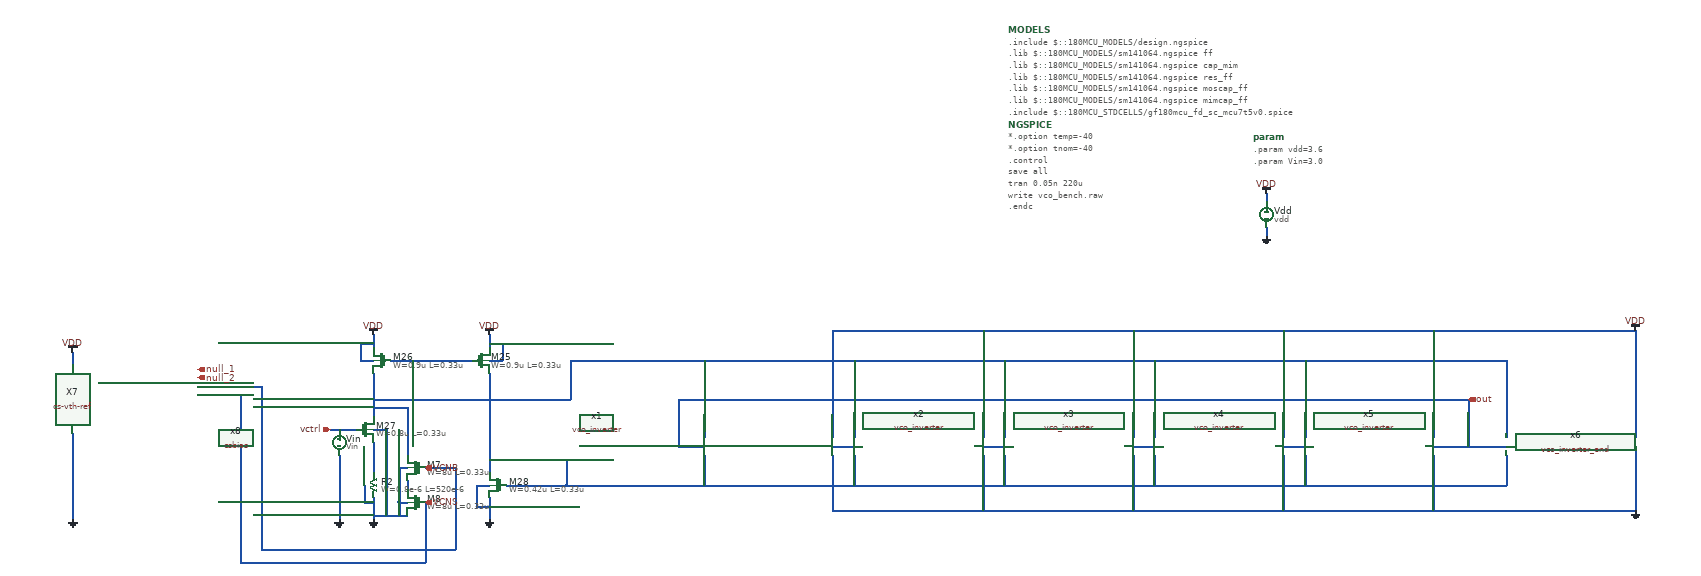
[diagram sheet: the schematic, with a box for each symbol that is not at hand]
v {xschem version=3.4.5 file_version=1.2
}
G {}
K {}
V {}
S {}
E {}
N 300 -460 300 -350 {
lab=out}
N 300 -350 360 -350 {
lab=out}
N 1670 -940 1670 -920 {
lab=VDD}
N 1670 -860 1670 -840 {
lab=GND}
N -410 -520 -410 -420 {
lab=#net1}
N -410 -610 -410 -580 {
lab=VDD}
N -140 -610 -140 -580 {
lab=VDD}
N -140 -590 -110 -590 {
lab=VDD}
N -110 -590 -110 -550 {
lab=VDD}
N -140 -550 -110 -550 {
lab=VDD}
N -440 -550 -410 -550 {
lab=VDD}
N -440 -590 -440 -550 {
lab=VDD}
N -440 -590 -410 -590 {
lab=VDD}
N 50 -550 50 -460 {
lab=#net1}
N -140 -520 -140 -290 {
lab=#net2}
N -140 -230 -140 -180 {
lab=GND}
N -410 -360 -410 -290 {
lab=#net3}
N -410 -230 -410 -180 {
lab=GND}
N -410 -390 -380 -390 {
lab=GND}
N -380 -390 -380 -200 {
lab=GND}
N -410 -440 -330 -440 {
lab=#net1}
N -330 -440 -330 -330 {
lab=#net1}
N -170 -260 -140 -260 {
lab=GND}
N -170 -210 -140 -210 {
lab=GND}
N -140 -320 40 -320 {
lab=#net2}
N -100 -260 40 -260 {
lab=#net2}
N -510 -390 -490 -390 {
lab=vctrl}
N -490 -390 -450 -390 {
lab=vctrl}
N 660 -350 710 -350 {
lab=#net4}
N 1010 -350 1060 -350 {
lab=#net5}
N 1360 -350 1410 -350 {
lab=#net6}
N 1710 -350 1760 -350 {
lab=#net7}
N 2060 -350 2230 -350 {
lab=out}
N 300 -460 2140 -460 {
lab=out}
N 2140 -460 2140 -350 {
lab=out}
N 40 -320 40 -260 {
lab=#net2}
N 40 -260 2230 -260 {
lab=#net2}
N 360 -330 360 -260 {
lab=#net2}
N 710 -330 710 -260 {
lab=#net2}
N 1060 -330 1060 -260 {
lab=#net2}
N 1410 -330 1410 -260 {
lab=#net2}
N 1760 -330 1760 -260 {
lab=#net2}
N 2230 -330 2230 -260 {
lab=#net2}
N 50 -550 2230 -550 {
lab=#net1}
N 2230 -550 2230 -370 {
lab=#net1}
N 360 -550 360 -370 {
lab=#net1}
N 710 -550 710 -370 {
lab=#net1}
N 1060 -550 1060 -370 {
lab=#net1}
N 1410 -550 1410 -370 {
lab=#net1}
N 1760 -550 1760 -370 {
lab=#net1}
N 660 -330 660 -200 {
lab=GND}
N 660 -200 2530 -200 {
lab=GND}
N 2530 -330 2530 -200 {
lab=GND}
N 660 -620 660 -370 {
lab=VDD}
N 660 -620 2530 -620 {
lab=VDD}
N 2530 -620 2530 -370 {
lab=VDD}
N 1010 -620 1010 -370 {
lab=VDD}
N 1360 -620 1360 -370 {
lab=VDD}
N 1710 -620 1710 -370 {
lab=VDD}
N 2060 -620 2060 -370 {
lab=VDD}
N 2530 -350 2530 -330 {
lab=GND}
N 2060 -330 2060 -200 {
lab=GND}
N 1710 -330 1710 -200 {
lab=GND}
N 1360 -330 1360 -200 {
lab=GND}
N 1010 -330 1010 -200 {
lab=GND}
N -430 -260 -430 -220 {
lab=GND}
N -430 -220 -410 -220 {
lab=GND}
N -490 -330 -490 -180 {
lab=GND}
N -350 -300 -330 -300 {
lab=GND}
N -350 -220 -330 -220 {
lab=GND}
N -330 -270 -330 -250 {
lab=#net8}
N -350 -300 -350 -220 {
lab=GND}
N -370 -550 -180 -550 {
lab=#net1}
N -410 -460 50 -460 {
lab=#net1}
N -320 -550 -320 -460 {
lab=#net1}
N -170 -260 -170 -210 {
lab=GND}
N -410 -190 -330 -190 {
lab=GND}
N -350 -220 -350 -190 {
lab=GND}
N -380 -200 -380 -190 {
lab=GND}
N -1110 -570 -1110 -540 {
lab=VDD}
N -1110 -380 -1110 -180 {
lab=GND}
N -1050 -500 -980 -500 {
lab=#net9}
N -820 -490 -670 -490 {
lab=VCNB}
N -670 -490 -670 -110 {
lab=VCNB}
N -670 -110 -220 -110 {
lab=VCNB}
N -220 -300 -220 -110 {
lab=VCNB}
N -290 -300 -220 -300 {
lab=VCNB}
N -820 -470 -720 -470 {
lab=VCNS}
N -720 -470 -720 -80 {
lab=VCNS}
N -720 -80 -290 -80 {
lab=VCNS}
N -290 -220 -290 -80 {
lab=VCNS}
C {devices/opin.sym} 2140 -460 0 0 {name=p1 lab=out}
C {devices/code_shown.sym} 1070 -1320 0 0 {name=MODELS only_toplevel=true
format="tcleval( @value )"
value="
.include $::180MCU_MODELS/design.ngspice
.lib $::180MCU_MODELS/sm141064.ngspice ff
.lib $::180MCU_MODELS/sm141064.ngspice cap_mim
.lib $::180MCU_MODELS/sm141064.ngspice res_ff
.lib $::180MCU_MODELS/sm141064.ngspice moscap_ff
.lib $::180MCU_MODELS/sm141064.ngspice mimcap_ff
.include $::180MCU_STDCELLS/gf180mcu_fd_sc_mcu7t5v0.spice
"}
C {devices/code_shown.sym} 1640 -1070 0 0 {name=param only_toplevel=false value="
.param vdd=3.6
.param Vin=3.0"}
C {devices/code_shown.sym} 1070 -1100 0 0 {name=NGSPICE only_toplevel=true
value="
*.option temp=-40
*.option tnom=-40
.control
save all
tran  0.05n 220u
write vco_bench.raw
.endc
"}
C {devices/vdd.sym} 1670 -940 0 0 {name=l13 lab=VDD}
C {devices/gnd.sym} 1670 -840 0 0 {name=l20 lab=GND}
C {devices/vsource.sym} 1670 -890 0 0 {name=Vdd value=vdd}
C {symbols/pfet_03v3.sym} -160 -550 0 0 {name=M25
L=0.33u
W=0.9u
nf=1
m=1
ad="'int((nf+1)/2) * W/nf * 0.18u'"
pd="'2*int((nf+1)/2) * (W/nf + 0.18u)'"
as="'int((nf+2)/2) * W/nf * 0.18u'"
ps="'2*int((nf+2)/2) * (W/nf + 0.18u)'"
nrd="'0.18u / W'" nrs="'0.18u / W'"
sa=0 sb=0 sd=0
model=pfet_03v3
spiceprefix=X
}
C {symbols/pfet_03v3.sym} -390 -550 0 1 {name=M26
L=0.33u
W=0.9u
nf=1
m=1
ad="'int((nf+1)/2) * W/nf * 0.18u'"
pd="'2*int((nf+1)/2) * (W/nf + 0.18u)'"
as="'int((nf+2)/2) * W/nf * 0.18u'"
ps="'2*int((nf+2)/2) * (W/nf + 0.18u)'"
nrd="'0.18u / W'" nrs="'0.18u / W'"
sa=0 sb=0 sd=0
model=pfet_03v3
spiceprefix=X
}
C {symbols/nfet_03v3.sym} -430 -390 0 0 {name=M27
L=0.33u
W=0.8u
nf=1
m=1
ad="'int((nf+1)/2) * W/nf * 0.18u'"
pd="'2*int((nf+1)/2) * (W/nf + 0.18u)'"
as="'int((nf+2)/2) * W/nf * 0.18u'"
ps="'2*int((nf+2)/2) * (W/nf + 0.18u)'"
nrd="'0.18u / W'" nrs="'0.18u / W'"
sa=0 sb=0 sd=0
model=nfet_03v3
spiceprefix=X
}
C {symbols/nfet_03v3.sym} -120 -260 0 1 {name=M28
L=0.33u
W=0.42u
nf=1
m=1
ad="'int((nf+1)/2) * W/nf * 0.18u'"
pd="'2*int((nf+1)/2) * (W/nf + 0.18u)'"
as="'int((nf+2)/2) * W/nf * 0.18u'"
ps="'2*int((nf+2)/2) * (W/nf + 0.18u)'"
nrd="'0.18u / W'" nrs="'0.18u / W'"
sa=0 sb=0 sd=0
model=nfet_03v3
spiceprefix=X
}
C {devices/vdd.sym} -410 -610 0 0 {name=l15 lab=VDD}
C {devices/vdd.sym} -140 -610 0 0 {name=l16 lab=VDD}
C {devices/gnd.sym} -410 -180 0 0 {name=l18 lab=GND}
C {devices/gnd.sym} -140 -180 0 0 {name=l19 lab=GND}
C {devices/ipin.sym} -510 -390 0 0 {name=p2 lab=vctrl}
C {devices/vsource.sym} -490 -360 0 0 {name=Vin value=Vin
}
C {vco_inverter.sym} 510 -350 0 0 {name=x1}
C {vco_inverter.sym} 860 -350 0 0 {name=x2}
C {vco_inverter.sym} 1210 -350 0 0 {name=x3}
C {vco_inverter.sym} 1560 -350 0 0 {name=x4}
C {vco_inverter.sym} 1910 -350 0 0 {name=x5}
C {vco_inverter_end.sym} 2380 -350 0 0 {name=x6}
C {devices/vdd.sym} 2530 -620 0 0 {name=l1 lab=VDD}
C {devices/gnd.sym} 2530 -200 0 0 {name=l2 lab=GND}
C {symbols/ppolyf_u.sym} -410 -260 0 0 {name=R2
W=0.8e-6
L=520e-6
model=ppolyf_u
spiceprefix=X
m=1}
C {devices/gnd.sym} -490 -180 0 0 {name=l10 lab=GND}
C {symbols/nfet_03v3.sym} -310 -300 0 1 {name=M7
L=0.33u
W=8u
nf=1
mult=1
ad="'int((nf+1)/2) * W/nf * 0.18u'"
pd="'2*int((nf+1)/2) * (W/nf + 0.18u)'"
as="'int((nf+2)/2) * W/nf * 0.18u'"
ps="'2*int((nf+2)/2) * (W/nf + 0.18u)'"
nrd="'0.18u / W'" nrs="'0.18u / W'"
sa=0 sb=0 sd=0
model=nfet_03v3
spiceprefix=X
}
C {symbols/nfet_03v3.sym} -310 -220 0 1 {name=M8
L=0.33u
W=8u
nf=1
mult=1
ad="'int((nf+1)/2) * W/nf * 0.18u'"
pd="'2*int((nf+1)/2) * (W/nf + 0.18u)'"
as="'int((nf+2)/2) * W/nf * 0.18u'"
ps="'2*int((nf+2)/2) * (W/nf + 0.18u)'"
nrd="'0.18u / W'" nrs="'0.18u / W'"
sa=0 sb=0 sd=0
model=nfet_03v3
spiceprefix=X
}
C {cs-vth-ref.sym} -1190 -360 0 0 {name=X7}
C {csbias.sym} -900 -500 0 0 {name=x8}
C {devices/vdd.sym} -1110 -570 0 0 {name=l3 lab=VDD}
C {devices/gnd.sym} -1110 -180 0 0 {name=l4 lab=GND}
C {devices/opin.sym} -820 -530 0 0 {name=p3 lab=null_1}
C {devices/opin.sym} -820 -510 0 0 {name=p4 lab=null_2}
C {devices/ipin.sym} -290 -300 0 1 {name=p5 lab=VCNB}
C {devices/ipin.sym} -290 -220 0 1 {name=p6 lab=VCNS}
